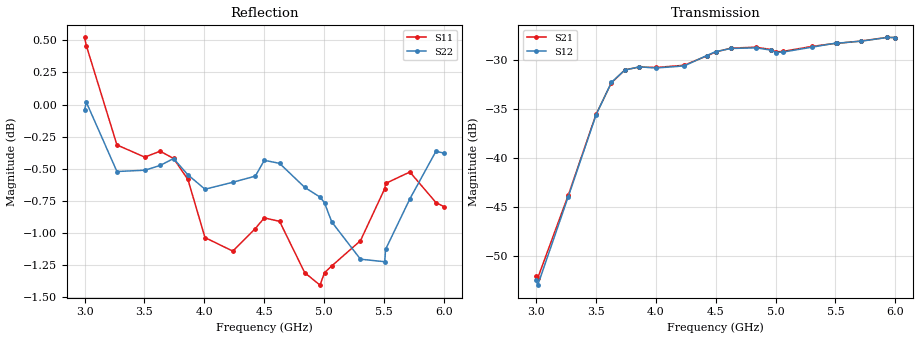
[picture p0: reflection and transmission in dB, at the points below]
!  26/11/2025  16:59:34
! Ref Plane: 0.000 mm
# MHZ S MA R  50
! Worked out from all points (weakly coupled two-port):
!   401 points, 3 GHz to 6 GHz, reference 50 ohm
!   highest |S21| = -27.72 dB at 5.933 GHz (marker M1); lowest = -52.2 dB at 3.015 GHz (marker M2)
!   lowest |S11| = -1.4 dB at 4.965 GHz (marker M3), VSWR 12.39, Z = 9.38 - j57.1 ohm
!   |S11| at or under -10 dB: nowhere
!   |S22| runs from -1.2 to 0.0 dB; largest |S21 - S12| = 0.0018
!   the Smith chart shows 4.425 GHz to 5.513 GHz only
!   S11 on the Smith chart (normalised r, x): 4.425 GHz: 0.11, +0.98; 4.628 GHz: 1.04, +4.24; 4.838 GHz: 0.56, -2.48; 5.062 GHz: 0.11, -0.70; 5.303 GHz: 0.06, -0.04; 5.513 GHz: 0.05, +0.56
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3000  1.062 -136.8  0.002499 47.7  0.002407 52.1  0.9953 -105.7
3015  1.054 -140.9  0.002452 46.5  0.002258 46.0  1.002 -108.8
3270  0.9645 152.8  0.006478 -18.0  0.006373 -13.6  0.9418 -170.5
3502.5  0.954 66.7  0.01674 -98.0  0.01662 -96.7  0.9429 112.5
3630  0.9591 11.9  0.02415 -153.9  0.02429 -152.8  0.9469 57.3
3742.5  0.9529 -37.5  0.0281 156.3  0.02805 157.7  0.9528 9.1
3862.5  0.9351 -85.2  0.02906 106.9  0.02912 108.5  0.939 -39.5
4005  0.8877 -136.6  0.02891 56.2  0.02873 57.3  0.927 -89.3
4237.5  0.877 149.5  0.02967 -15.6  0.02944 -13.5  0.9328 -161.9
4425  0.8949 90.6  0.03309 -72.5  0.03322 -71.0  0.9379 140.2
4500  0.9035 66.5  0.03463 -96.5  0.03479 -95.0  0.9513 117.2
4627.5  0.9007 25.2  0.03627 -137.1  0.03611 -135.9  0.9487 77.7
4837.5  0.8602 -42.2  0.03665 156.2  0.03638 157.8  0.9285 13.8
4965  0.8507 -81.5  0.03565 119.5  0.03539 121.0  0.9205 -22.4
5002.5  0.8602 -93.0  0.0347 109.2  0.03443 110.4  0.9158 -34.2
5062.5  0.8654 -109.8  0.0349 92.5  0.03463 93.7  0.9003 -52.2
5302.5  0.8852 -175.7  0.03698 26.0  0.03665 27.3  0.8707 -121.2
5505  0.9274 123.1  0.03837 -31.2  0.03849 -29.2  0.8687 -176.3
5512.5  0.9318 121.8  0.03831 -33.0  0.03842 -31.0  0.8784 -179.2
5715  0.9414 64.0  0.03943 -91.2  0.03933 -88.9  0.919 124.0
5932.5  0.916 1.6  0.04112 -153.4  0.04109 -151.7  0.959 67.2
6000  0.9126 -18.2  0.04106 -172.6  0.04105 -171.0  0.9574 50.0
